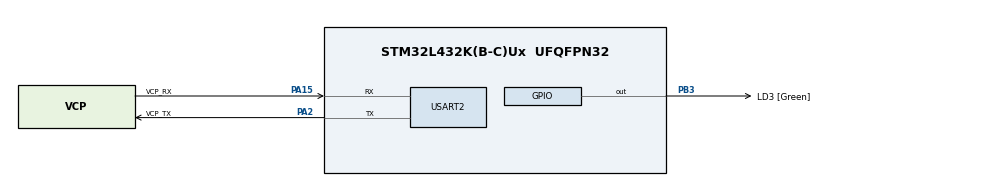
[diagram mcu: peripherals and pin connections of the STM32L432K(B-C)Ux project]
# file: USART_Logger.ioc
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Mcu.Family=STM32L4
Mcu.Name=STM32L432K(B-C)Ux
Mcu.Package=UFQFPN32
NVIC.PriorityGroup=NVIC_PRIORITYGROUP_4
NVIC.USART2_IRQn=true\:0\:0\:false\:false\:true\:true\:true\:true
PA0.GPIO_Label=MCO [High speed clock in]
PA0.Mode=HSE-External-Clock-Source-for-LittleOrca
PA0.Signal=RCC_CK_IN
PA13\ (JTMS-SWDIO).GPIO_Label=SWDIO
PA13\ (JTMS-SWDIO).Mode=Serial_Wire
PA13\ (JTMS-SWDIO).Signal=SYS_JTMS-SWDIO
PA14\ (JTCK-SWCLK).GPIO_Label=SWCLK
PA14\ (JTCK-SWCLK).Mode=Serial_Wire
PA14\ (JTCK-SWCLK).Signal=SYS_JTCK-SWCLK
PA15\ (JTDI).GPIO_Label=VCP_RX
PA15\ (JTDI).Mode=Asynchronous
PA15\ (JTDI).Signal=USART2_RX
PA2.GPIO_Label=VCP_TX
PA2.Mode=Asynchronous
PA2.Signal=USART2_TX
PB3\ (JTDO-TRACESWO).GPIO_Label=LD3 [Green]
PB3\ (JTDO-TRACESWO).Signal=GPIO_Output
PC14-OSC32_IN\ (PC14).Mode=LSE-External-Oscillator
PC14-OSC32_IN\ (PC14).Signal=RCC_OSC32_IN
PC15-OSC32_OUT\ (PC15).Mode=LSE-External-Oscillator
PC15-OSC32_OUT\ (PC15).Signal=RCC_OSC32_OUT
ProjectManager.HeapSize=0x200
ProjectManager.StackSize=0x400
ProjectManager.TargetToolchain=STM32CubeIDE
RCC.AHBFreq_Value=32000000
RCC.APB1Freq_Value=32000000
RCC.APB1TimFreq_Value=32000000
RCC.APB2Freq_Value=32000000
RCC.APB2TimFreq_Value=32000000
RCC.CortexFreq_Value=32000000
RCC.HCLKFreq_Value=32000000
RCC.HSE_VALUE=8000000
RCC.HSI16_VALUE=16000000
RCC.HSI48_VALUE=48000000
RCC.HSI_VALUE=16000000
RCC.MSI_VALUE=4000000
RCC.PLLMUL=RCC_PLLMUL_4
RCC.PLLN=16
RCC.SYSCLKFreq_VALUE=32000000
RCC.SYSCLKSource=RCC_SYSCLKSOURCE_PLLCLK
RCC.VCOOutputFreq_Value=64000000
USART2.VirtualMode-Asynchronous=VM_ASYNC
board=NUCLEO-L432KC

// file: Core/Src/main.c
/* USER CODE BEGIN Header */
/**
  ******************************************************************************
  * @file           : main.c
  * @brief          : Main program body
  ******************************************************************************
  * @attention
  *
  * Copyright (c) 2025 STMicroelectronics.
  * All rights reserved.
  *
  * This software is licensed under terms that can be found in the LICENSE file
  * in the root directory of this software component.
  * If no LICENSE file comes with this software, it is provided AS-IS.
  *
  ******************************************************************************
  */
/* USER CODE END Header */
#include "main.h"
#include "usart_cmd.h"

UART_HandleTypeDef huart2;

void SystemClock_Config(void);
static void MX_GPIO_Init(void);
static void MX_USART2_UART_Init(void);

int main(void)
{

  HAL_Init();
  SystemClock_Config();
  MX_GPIO_Init();
  MX_USART2_UART_Init();

  while (1)
  {
	  USART_StartReceive_IT();
  }

}

int __io_putchar(int ch)
{
    HAL_UART_Transmit(&huart2, (uint8_t *)&ch, 1, HAL_MAX_DELAY);
    return ch;
}

void SystemClock_Config(void)
{
	  RCC_ClkInitTypeDef RCC_ClkInitStruct = {0};
	  RCC_OscInitTypeDef RCC_OscInitStruct = {0};

	  /* MSI is enabled after System reset, activate PLL with MSI as source */
	  RCC_OscInitStruct.OscillatorType = RCC_OSCILLATORTYPE_MSI;
	  RCC_OscInitStruct.MSIState = RCC_MSI_ON;
	  RCC_OscInitStruct.MSIClockRange = RCC_MSIRANGE_6;
	  RCC_OscInitStruct.MSICalibrationValue = RCC_MSICALIBRATION_DEFAULT;
	  RCC_OscInitStruct.PLL.PLLState = RCC_PLL_ON;
	  RCC_OscInitStruct.PLL.PLLSource = RCC_PLLSOURCE_MSI;
	  RCC_OscInitStruct.PLL.PLLM = 1;
	  RCC_OscInitStruct.PLL.PLLN = 40;
	  RCC_OscInitStruct.PLL.PLLR = 2;
	  RCC_OscInitStruct.PLL.PLLP = 7;
	  RCC_OscInitStruct.PLL.PLLQ = 4;
	  if(HAL_RCC_OscConfig(&RCC_OscInitStruct) != HAL_OK)
	  {
	    /* Initialization Error */
	    while(1);
	  }

	  /* Select PLL as system clock source and configure the HCLK, PCLK1 and PCLK2
	     clocks dividers */
	  RCC_ClkInitStruct.ClockType = (RCC_CLOCKTYPE_SYSCLK | RCC_CLOCKTYPE_HCLK | RCC_CLOCKTYPE_PCLK1 | RCC_CLOCKTYPE_PCLK2);
	  RCC_ClkInitStruct.SYSCLKSource = RCC_SYSCLKSOURCE_PLLCLK;
	  RCC_ClkInitStruct.AHBCLKDivider = RCC_SYSCLK_DIV1;
	  RCC_ClkInitStruct.APB1CLKDivider = RCC_HCLK_DIV1;
	  RCC_ClkInitStruct.APB2CLKDivider = RCC_HCLK_DIV1;
	  if(HAL_RCC_ClockConfig(&RCC_ClkInitStruct, FLASH_LATENCY_4) != HAL_OK)
	  {
	    /* Initialization Error */
	    while(1);
	  }

  /** Enable MSI Auto calibration
  */
  HAL_RCCEx_EnableMSIPLLMode();
}

static void MX_USART2_UART_Init(void)
{

  huart2.Instance = USART2;
  huart2.Init.BaudRate = 115200;
  huart2.Init.WordLength = UART_WORDLENGTH_8B;
  huart2.Init.StopBits = UART_STOPBITS_1;
  huart2.Init.Parity = UART_PARITY_NONE;
  huart2.Init.Mode = UART_MODE_TX_RX;
  huart2.Init.HwFlowCtl = UART_HWCONTROL_NONE;
  huart2.Init.OverSampling = UART_OVERSAMPLING_16;
  huart2.Init.OneBitSampling = UART_ONE_BIT_SAMPLE_DISABLE;
  huart2.AdvancedInit.AdvFeatureInit = UART_ADVFEATURE_NO_INIT;
  if (HAL_UART_Init(&huart2) != HAL_OK)
  {
    Error_Handler();
  }

}

static void MX_GPIO_Init(void)
{
  GPIO_InitTypeDef GPIO_InitStruct = {0};

  /* GPIO Ports Clock Enable */
  __HAL_RCC_GPIOC_CLK_ENABLE();
  __HAL_RCC_GPIOA_CLK_ENABLE();
  __HAL_RCC_GPIOB_CLK_ENABLE();

  /*Configure GPIO pin Output Level */
  HAL_GPIO_WritePin(LD3_GPIO_Port, LD3_Pin, GPIO_PIN_RESET);

  /*Configure GPIO pin : LD3_Pin */
  GPIO_InitStruct.Pin = LD3_Pin;
  GPIO_InitStruct.Mode = GPIO_MODE_OUTPUT_PP;
  GPIO_InitStruct.Pull = GPIO_NOPULL;
  GPIO_InitStruct.Speed = GPIO_SPEED_FREQ_LOW;
  HAL_GPIO_Init(LD3_GPIO_Port, &GPIO_InitStruct);

}

void Error_Handler(void)
{
  __disable_irq();
  while (1)
  {
  }
}
